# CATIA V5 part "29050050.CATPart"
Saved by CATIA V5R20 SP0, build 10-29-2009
Part number: 29050050
Definition: NONE
Nomenclature: 29050050
Source: Unknown
Description: 29050050
Bounding box of the stored display mesh (mm): x -25 to 44.548, y -39 to 73.548, z -29 to 29
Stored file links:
  C:\Users\Utente\Desktop\IO LAVORO\3D X SITO CF\X SITO\PLASTICA\RF1\29050050.CATPart

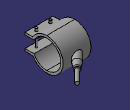
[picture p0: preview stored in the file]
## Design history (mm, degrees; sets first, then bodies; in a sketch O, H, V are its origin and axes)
Body1 "29050050" (main body)
  Solid1: solid without history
